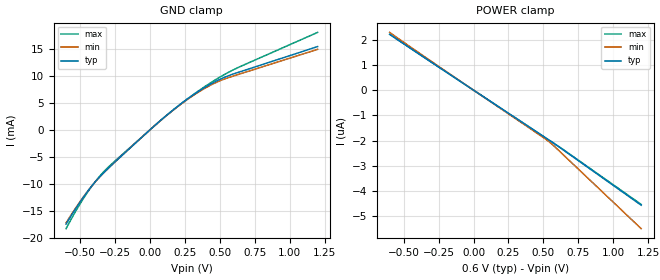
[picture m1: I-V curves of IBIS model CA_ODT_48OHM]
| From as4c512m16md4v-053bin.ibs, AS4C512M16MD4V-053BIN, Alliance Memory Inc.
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|   MODEL: CA_ODT_48OHM
[Model]   CA_ODT_48OHM
Model_type   Input
Vinl   = 0.080V
Vinh   = 0.220V
|   typ   min   max
C_comp   0.525pF   0.473pF   0.578pF
[Voltage Range]   0.600V   0.570V   0.650V
[Temperature Range]   25.0   85.0   -25.0
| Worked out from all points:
|   GND clamp passes 1 mA (typ) near -0.04 V on its own axis
[GND Clamp]
|   Voltage   I(typ)   I(min)   I(max)
-600mV    -17.5mA    -17.27mA   -18.35mA
-530mV    -14.57mA   -14.46mA   -15.04mA
-460mV    -11.92mA   -11.89mA   -12.11mA
-390mV    -9.606mA   -9.625mA   -9.577mA
-330mV    -7.942mA   -7.95mA    -7.761mA
40mV      935.3uA    924.7uA    918.6uA
160mV     3.582mA    3.536mA    3.549mA
280mV     5.954mA    5.86mA     5.974mA
420mV     8.293mA    8.109mA    8.504mA
550mV     9.935mA    9.604mA    10.52mA
650mV     10.83mA    10.44mA    11.8mA
1.2V      15.47mA    14.96mA    18.1mA
[POWER Clamp]
|   Voltage   I(typ)   I(min)   I(max)
-600mV    2.209uA    2.286uA    2.21uA
540mV     -1.977uA   -2.04uA    -1.975uA
650mV     -2.398uA   -2.599uA   -2.382uA
1.2V      -4.555uA   -5.484uA   -4.524uA
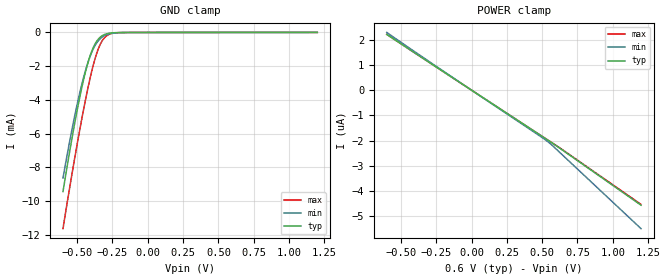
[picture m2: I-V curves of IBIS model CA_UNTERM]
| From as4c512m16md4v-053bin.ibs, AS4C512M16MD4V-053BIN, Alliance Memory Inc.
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|   MODEL: CA_UNTERM
[Model]   CA_UNTERM
Model_type   Input
Vinl   = 0.080V
Vinh   = 0.220V
|   typ   min   max
C_comp   0.525pF   0.473pF   0.578pF
[Voltage Range]   0.600V   0.570V   0.650V
[Temperature Range]   25.0   85.0   -25.0
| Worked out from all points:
|   GND clamp passes 1 mA (typ) near -0.39 V on its own axis
[GND Clamp]
|   Voltage   I(typ)   I(min)   I(max)
-600mV    -9.434mA   -8.63mA    -11.64mA
-550mV    -6.93mA    -6.337mA   -9.071mA
-510mV    -5.067mA   -4.664mA   -7.116mA
-470mV    -3.391mA   -3.183mA   -5.263mA
-430mV    -1.992mA   -1.958mA   -3.554mA
-400mV    -1.191mA   -1.248mA   -2.417mA
-360mV    -504.2uA   -602.3uA   -1.204mA
-330mV    -235.6uA   -319.5uA   -599.3uA
-290mV    -77.05uA   -125.7uA   -190.3uA
-250mV    -23.77uA   -46.49uA   -52uA
-170mV    -2.45uA    -6.01uA    -3.627uA
1.2V      4.4uA      4.55uA     4.397uA
[POWER Clamp]
|   Voltage   I(typ)   I(min)   I(max)
-600mV    2.209uA    2.286uA    2.21uA
540mV     -1.977uA   -2.04uA    -1.975uA
650mV     -2.398uA   -2.599uA   -2.382uA
1.2V      -4.555uA   -5.484uA   -4.524uA
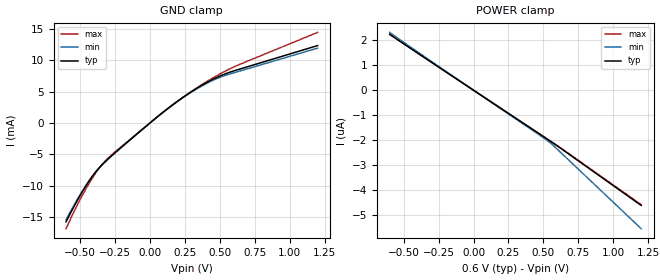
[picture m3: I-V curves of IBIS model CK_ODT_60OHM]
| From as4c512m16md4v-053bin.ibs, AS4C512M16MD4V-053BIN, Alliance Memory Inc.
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|   MODEL: CK_ODT_60OHM
[Model]   CK_ODT_60OHM
Model_type   Input
Vinl   = 0.080V
Vinh   = 0.220V
|   typ   min   max
C_comp   0.528pF   0.475pF   0.581pF
[Voltage Range]   0.600V   0.570V   0.650V
[Temperature Range]   25.0   85.0   -25.0
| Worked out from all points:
|   GND clamp passes 1 mA (typ) near -0.05 V on its own axis
[GND Clamp]
|   Voltage   I(typ)   I(min)   I(max)
-600mV    -15.8mA    -15.46mA   -16.9mA
-520mV    -12.4mA    -12.23mA   -13.13mA
-450mV    -9.763mA   -9.724mA   -10.22mA
-390mV    -7.874mA   -7.904mA   -8.065mA
-330mV    -6.397mA   -6.421mA   -6.325mA
-250mV    -4.771mA   -4.761mA   -4.631mA
20mV      376.5uA    372.3uA    369.3uA
240mV     4.156mA    4.096mA    4.15mA
400mV     6.391mA    6.258mA    6.53mA
540mV     7.862mA    7.608mA    8.298mA
650mV     8.663mA    8.348mA    9.44mA
1.2V      12.38mA    11.97mA    14.48mA
[POWER Clamp]
|   Voltage   I(typ)   I(min)   I(max)
-600mV    2.234uA    2.311uA    2.235uA
540mV     -1.999uA   -2.062uA   -1.998uA
650mV     -2.425uA   -2.626uA   -2.409uA
1.2V      -4.606uA   -5.535uA   -4.574uA
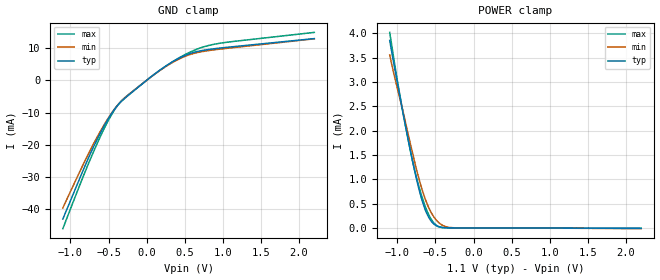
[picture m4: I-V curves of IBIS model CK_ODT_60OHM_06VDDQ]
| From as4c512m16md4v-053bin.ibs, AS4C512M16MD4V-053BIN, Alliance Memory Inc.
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|   MODEL: CK_ODT_60OHM_06VDDQ
[Model]   CK_ODT_60OHM_06VDDQ
Model_type   Input
Vinl   = 0.080V
Vinh   = 0.220V
|   typ   min   max
C_comp   0.528pF   0.475pF   0.581pF
[Voltage Range]   1.100V   1.060V   1.170V
[Temperature Range]   25.0   125.0   -40.0
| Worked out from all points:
|   GND clamp passes 1 mA (typ) near -0.05 V on its own axis
|   POWER clamp passes 1 mA (typ) near -0.75 V on its own axis
[GND Clamp]
|   Voltage   I(typ)   I(min)   I(max)
-1.1V     -42.96mA   -39.51mA   -45.94mA
-710mV    -21.23mA   -20.25mA   -22.82mA
-580mV    -15.08mA   -14.65mA   -16.02mA
-470mV    -10.63mA   -10.48mA   -11.04mA
-320mV    -6.286mA   -6.193mA   -6.103mA
40mV      761.1uA    731.7uA    743.1uA
240mV     4.234mA    4.083mA    4.196mA
440mV     7.005mA    6.763mA    7.142mA
600mV     8.511mA    8.193mA    9.042mA
770mV     9.38mA     9.038mA    10.5mA
1.05V     10.2mA     9.888mA    11.77mA
2.2V      12.91mA    12.84mA    14.83mA
[POWER Clamp]
|   Voltage   I(typ)   I(min)   I(max)
-1.1V     3.851mA    3.554mA    4.016mA
-1.01V    3.068mA    2.931mA    3.123mA
-940mV    2.475mA    2.485mA    2.495mA
-840mV    1.679mA    1.801mA    1.669mA
-770mV    1.153mA    1.339mA    1.17mA
-700mV    699.8uA    918.7uA    757.8uA
-630mV    358.7uA    578.1uA    426.1uA
-560mV    148.8uA    328uA      188.9uA
-490mV    45.81uA    162.6uA    57.53uA
-390mV    5.639uA    40.34uA    5.673uA
-260mV    1.093uA    3.432uA    1.039uA
2.2V      -8.447uA   -15.17uA   -8.228uA
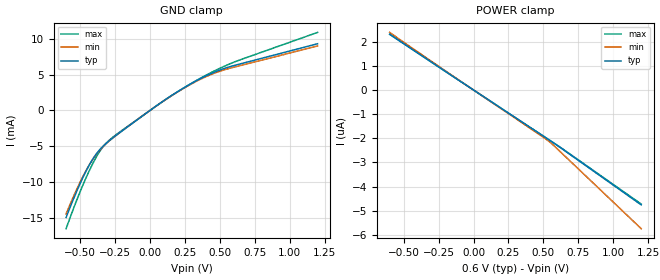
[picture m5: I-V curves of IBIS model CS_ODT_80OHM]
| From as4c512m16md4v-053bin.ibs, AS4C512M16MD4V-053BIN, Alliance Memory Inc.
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|   MODEL: CS_ODT_80OHM
[Model]   CS_ODT_80OHM
Model_type   Input
Vinl   = 0.080V
Vinh   = 0.220V
|   typ   min   max
C_comp   0.564pF   0.508pF   0.620pF
[Voltage Range]   0.600V   0.570V   0.650V
[Temperature Range]   25.0   85.0   -25.0
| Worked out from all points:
|   GND clamp passes 1 mA (typ) near -0.07 V on its own axis
[GND Clamp]
|   Voltage   I(typ)   I(min)   I(max)
-600mV    -14.89mA   -14.39mA   -16.44mA
-500mV    -10.19mA   -9.988mA   -11.32mA
-460mV    -8.546mA   -8.462mA   -9.488mA
-420mV    -7.112mA   -7.123mA   -7.813mA
-380mV    -5.948mA   -6.007mA   -6.345mA
-340mV    -5.057mA   -5.11mA    -5.164mA
-260mV    -3.731mA   -3.735mA   -3.635mA
120mV     1.635mA    1.615mA    1.615mA
260mV     3.345mA    3.295mA    3.348mA
400mV     4.791mA    4.692mA    4.895mA
580mV     6.135mA    5.915mA    6.553mA
1.2V      9.286mA    8.978mA    10.86mA
[POWER Clamp]
|   Voltage   I(typ)   I(min)   I(max)
-600mV    2.308uA    2.386uA    2.308uA
540mV     -2.065uA   -2.13uA    -2.064uA
650mV     -2.505uA   -2.717uA   -2.488uA
1.2V      -4.759uA   -5.745uA   -4.723uA
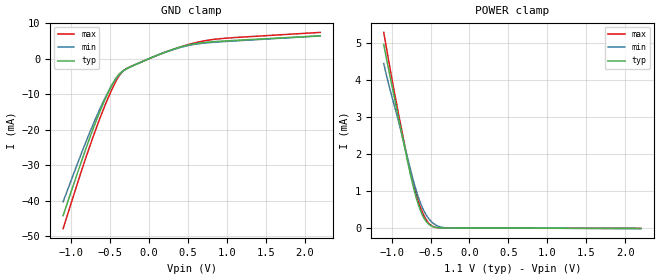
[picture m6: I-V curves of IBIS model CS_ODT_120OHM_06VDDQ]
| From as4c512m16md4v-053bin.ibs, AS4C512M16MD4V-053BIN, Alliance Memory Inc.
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|   MODEL: CS_ODT_120OHM_06VDDQ
[Model]   CS_ODT_120OHM_06VDDQ
Model_type   Input
Vinl   = 0.080V
Vinh   = 0.220V
|   typ   min   max
C_comp   0.564pF   0.508pF   0.620pF
[Voltage Range]   1.100V   1.060V   1.170V
[Temperature Range]   25.0   125.0   -40.0
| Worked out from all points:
|   GND clamp passes 1 mA (typ) near -0.10 V on its own axis
|   POWER clamp passes 1 mA (typ) near -0.71 V on its own axis
[GND Clamp]
|   Voltage   I(typ)   I(min)   I(max)
-1.1V     -44.13mA   -40.22mA   -47.8mA
-820mV    -26.05mA   -24.09mA   -28.6mA
-700mV    -18.84mA   -17.68mA   -21.02mA
-600mV    -13.37mA   -12.76mA   -15.17mA
-510mV    -8.964mA   -8.811mA   -10.39mA
-440mV    -6.09mA    -6.219mA   -7.105mA
-370mV    -4.088mA   -4.273mA   -4.461mA
-310mV    -3.11mA    -3.172mA   -3.089mA
200mV     1.793mA    1.729mA    1.771mA
580mV     4.181mA    4.027mA    4.414mA
970mV     4.999mA    4.838mA    5.75mA
2.2V      6.458mA    6.423mA    7.417mA
[POWER Clamp]
|   Voltage   I(typ)   I(min)   I(max)
-1.1V     4.96mA     4.444mA    5.287mA
-1.04V    4.311mA    3.913mA    4.562mA
-940mV    3.275mA    3.119mA    3.408mA
-820mV    2.064mA    2.11mA     2.117mA
-750mV    1.376mA    1.524mA    1.451mA
-690mV    869.2uA    1.061mA    964.3uA
-630mV    479.1uA    684.3uA    568.6uA
-570mV    224.3uA    406.8uA    279.7uA
-500mV    69.96uA    197.1uA    86.74uA
-400mV    8.221uA    49.73uA    8.449uA
-280mV    1.305uA    5.057uA    1.216uA
2.2V      -8.728uA   -15.86uA   -8.498uA
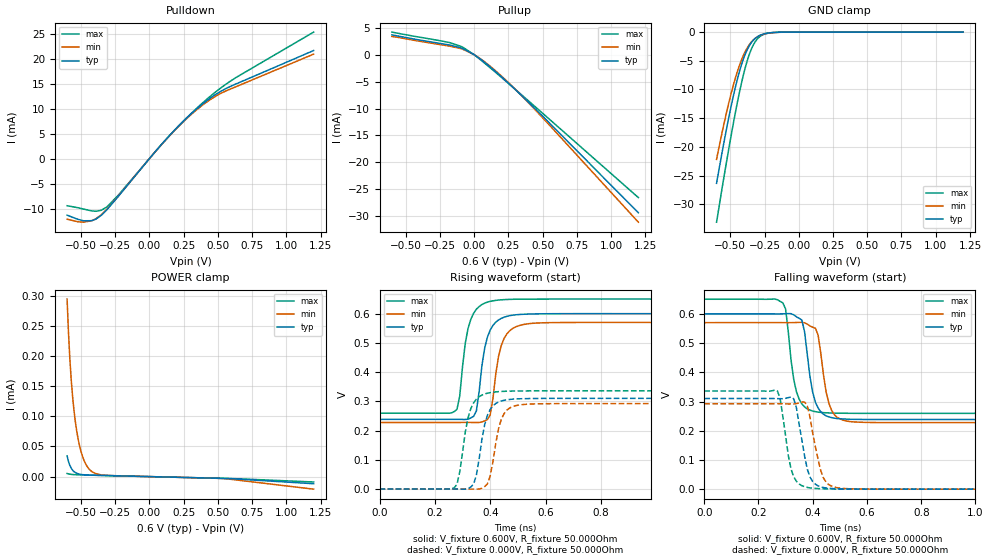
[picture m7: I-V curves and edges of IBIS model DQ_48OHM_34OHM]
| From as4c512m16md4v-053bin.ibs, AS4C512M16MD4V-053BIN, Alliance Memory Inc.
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|   MODEL: DQ_48OHM_34OHM
[Model]   DQ_48OHM_34OHM
Model_type   I/O
Polarity   Non-Inverting
Enable   Active-High
Vinl   = 0.080V
Vinh   = 0.220V
Vmeas   = 0.150V
Vref   = 0.150V
Cref   = 0.000pF
Rref   = 50.000Ohm
|   typ   min   max
C_comp   0.875pF   0.788pF   0.963pF
[Voltage Range]   0.600V   0.570V   0.650V
[Temperature Range]   25.0   85.0   -25.0
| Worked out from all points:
|   slope of the pulldown table from 0 to 0.09 V, typ, clamps not added: 31.1 ohm
|   slope of the pullup table from 0 to 0.09 V, typ, clamps not added: 52.7 ohm
|   GND clamp passes 1 mA (typ) near -0.31 V on its own axis
|   rising waveform, V_fixture 0.600V, R_fixture 50.000Ohm: 20-80 % time 36.6ps typ, 36.8ps min, 35.3ps max; typ from 0.238 V to 0.6 V
|   falling waveform, V_fixture 0.600V, R_fixture 50.000Ohm: 20-80 % time 34.7ps typ, 35.1ps min, 33.3ps max; typ from 0.6 V to 0.238 V
|   rising waveform, V_fixture 0.000V, R_fixture 50.000Ohm: 20-80 % time 36.1ps typ, 35.9ps min, 36.7ps max; typ from 0 V to 0.31 V
|   falling waveform, V_fixture 0.000V, R_fixture 50.000Ohm: 20-80 % time 37ps typ, 39.2ps min, 34.1ps max; typ from 0.31 V to 0 V
[Pulldown]
|   Voltage   I(typ)   I(min)   I(max)
-600mV    -11.29mA   -12.1mA    -9.399mA
-480mV    -12.41mA   -12.69mA   -10.07mA
-420mV    -12.4mA    -12.4mA    -10.44mA
-350mV    -11.31mA   -11.2mA    -10.3mA
-310mV    -10.22mA   -10.13mA   -9.646mA
-230mV    -7.655mA   -7.604mA   -7.404mA
130mV     4.124mA    4.073mA    4.076mA
270mV     8.079mA    7.954mA    8.096mA
400mV     11.19mA    10.96mA    11.44mA
490mV     12.95mA    12.6mA     13.49mA
580mV     14.32mA    13.81mA    15.3mA
1.2V      21.66mA    20.94mA    25.35mA
[Pullup]
|   Voltage   I(typ)   I(min)   I(max)
-600mV    3.666mA    3.362mA    4.175mA
-180mV    1.791mA    1.583mA    2.24mA
-100mV    1.29mA     1.134mA    1.576mA
0V        0A         0A         0A
80mV      -1.505mA   -1.39mA    -1.643mA
220mV     -4.564mA   -4.445mA   -4.653mA
400mV     -8.893mA   -8.998mA   -8.629mA
1.2V      -29.33mA   -31.08mA   -26.52mA
[GND Clamp]
|   Voltage   I(typ)   I(min)   I(max)
-600mV    -26.36mA   -22.19mA   -33.14mA
-550mV    -19.73mA   -16.43mA   -25.84mA
-510mV    -14.79mA   -12.27mA   -20.24mA
-470mV    -10.36mA   -8.615mA   -14.96mA
-430mV    -6.627mA   -5.609mA   -10.17mA
-390mV    -3.805mA   -3.349mA   -6.151mA
-360mV    -2.341mA   -2.151mA   -3.819mA
-320mV    -1.14mA    -1.122mA   -1.755mA
-280mV    -524.1uA   -555.5uA   -715.7uA
-230mV    -184.4uA   -215.6uA   -213.3uA
-140mV    -20.29uA   -29.99uA   -17.96uA
1.2V      6.836uA    7.386uA    6.714uA
[POWER Clamp]
|   Voltage   I(typ)   I(min)   I(max)
-600mV    34.27uA    294.1uA    5.169uA
-590mV    25uA       238.9uA    4.47uA
-570mV    13.84uA    160.6uA    3.674uA
-560mV    10.58uA    132.6uA    3.444uA
-540mV    6.655uA    91.24uA    3.146uA
-520mV    4.678uA    62.84uA    2.957uA
-490mV    3.339uA    35.2uA     2.748uA
-460mV    2.772uA    19.1uA     2.569uA
-420mV    2.39uA     8.47uA     2.342uA
-300mV    1.671uA    1.938uA    1.671uA
560mV     -3.13uA    -3.595uA   -3.086uA
1.2V      -11.8uA    -20.82uA   -8.926uA
[Ramp]
R_load = 50.000Ohm
|   typ   min   max
dV/dt_r   0.217V/40.000ps   0.205V/40.000ps   0.234V/30.000ps
dV/dt_f   0.217V/30.000ps   0.205V/30.000ps   0.234V/30.000ps
|Slew_r   5.425V/ns   5.134V/ns   7.810V/ns
|Slew_f   7.231V/ns   6.843V/ns   7.807V/ns
[Rising Waveform]
V_fixture = 0.600V
V_fixture_min = 0.570V
V_fixture_max = 0.650V
R_fixture = 50.000Ohm
L_fixture = 0.000nH
C_fixture = 0.000pF
|dV/dt_r   0.217V/40.000ps   0.205V/40.000ps   0.234V/30.000ps
|Slew_r   5.425V/ns   5.134V/ns   7.810V/ns
|   Time   V(typ)   V(min)   V(max)
0s        238.3mV    227.7mV    259.5mV
280ps     238.5mV    227.8mV    272.9mV
310ps     238.1mV    227.9mV    499.2mV
340ps     248.8mV    227.7mV    601.4mV
380ps     482.2mV    233.2mV    636.1mV
400ps     543.9mV    253.8mV    642.3mV
440ps     583.9mV    491mV      647.4mV
490ps     595.8mV    554mV      649.4mV
610ps     599.8mV    569.2mV    649.9mV
5ns       600mV      570mV      650mV
[Falling Waveform]
V_fixture = 0.600V
V_fixture_min = 0.570V
V_fixture_max = 0.650V
R_fixture = 50.000Ohm
L_fixture = 0.000nH
C_fixture = 0.000pF
|dV/dt_f   0.217V/30.000ps   0.205V/30.000ps   0.234V/30.000ps
|Slew_f   7.231V/ns   6.843V/ns   7.807V/ns
|   Time   V(typ)   V(min)   V(max)
0s        599.9mV    569.9mV    649.9mV
290ps     600.1mV    569.9mV    637.5mV
300ps     600.6mV    569.9mV    616.6mV
330ps     596.7mV    570.1mV    375.4mV
360ps     578.5mV    571mV      291.9mV
400ps     331.3mV    554.2mV    267.4mV
430ps     264.5mV    463.7mV    262.6mV
470ps     244.7mV    269.2mV    260.6mV
560ps     238.9mV    229.8mV    259.6mV
5ns       238.4mV    227.8mV    259.5mV
[Rising Waveform]
V_fixture = 0.000V
V_fixture_min = 0.000V
V_fixture_max = 0.000V
R_fixture = 50.000Ohm
L_fixture = 0.000nH
C_fixture = 0.000pF
|dV/dt_r   0.186V/30.000ps   0.175V/30.000ps   0.202V/30.000ps
|Slew_r   6.205V/ns   5.847V/ns   6.720V/ns
|   Time   V(typ)   V(min)   V(max)
0s        3.602uV    10.71uV    1.531uV
270ps     74.81uV    11.77uV    4.598mV
290ps     -195.7uV   38.56uV    59.19mV
330ps     7.147mV    -165.4uV   275.4mV
350ps     47.63mV    -365.8uV   307.6mV
390ps     252.4mV    17.62mV    328mV
430ps     297.9mV    206.1mV    333.3mV
470ps     306.5mV    277mV      334.9mV
570ps     309.9mV    291.5mV    335.9mV
5ns       310.2mV    292.4mV    336mV
[Falling Waveform]
V_fixture = 0.000V
V_fixture_min = 0.000V
V_fixture_max = 0.000V
R_fixture = 50.000Ohm
L_fixture = 0.000nH
C_fixture = 0.000pF
|dV/dt_f   0.186V/40.000ps   0.175V/40.000ps   0.202V/40.000ps
|Slew_f   4.653V/ns   4.385V/ns   5.039V/ns
|   Time   V(typ)   V(min)   V(max)
0s        310.2mV    292.3mV    335.9mV
270ps     309.8mV    292.4mV    336mV
280ps     309.5mV    292.4mV    309.2mV
310ps     313.3mV    291.7mV    115mV
330ps     309mV      291.7mV    42.43mV
380ps     68.48mV    284.9mV    5.936mV
410ps     16.83mV    144.2mV    2.465mV
450ps     4.049mV    23.33mV    915.8uV
540ps     435uV      1.228mV    53.84uV
5ns       3.996uV    11.07uV    1.926uV
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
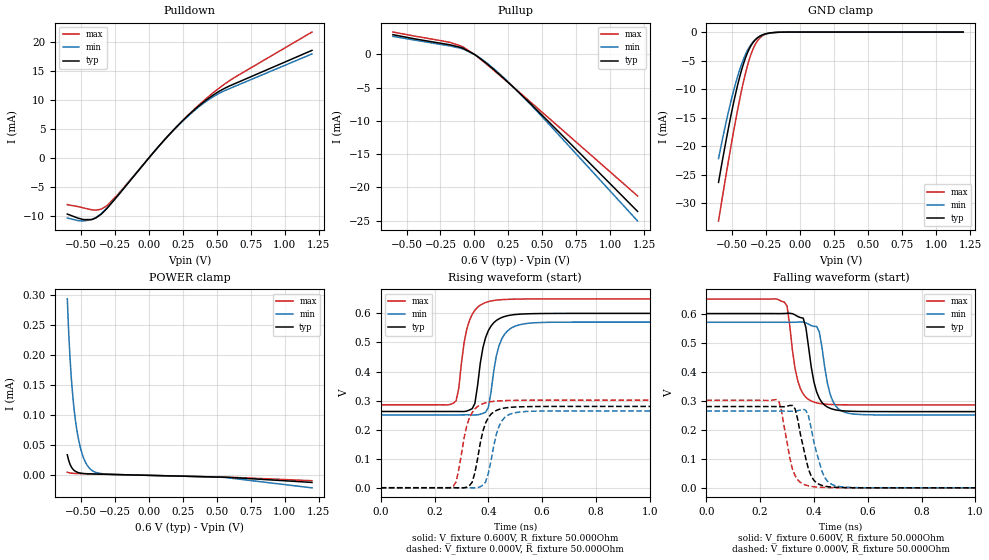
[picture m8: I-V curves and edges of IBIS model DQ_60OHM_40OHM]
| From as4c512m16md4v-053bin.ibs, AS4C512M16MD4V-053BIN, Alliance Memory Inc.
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|   MODEL: DQ_60OHM_40OHM
[Model]   DQ_60OHM_40OHM
Model_type   I/O
Polarity   Non-Inverting
Enable   Active-High
Vinl   = 0.080V
Vinh   = 0.220V
Vmeas   = 0.150V
Vref   = 0.150V
Cref   = 0.000pF
Rref   = 50.000Ohm
|   typ   min   max
C_comp   0.875pF   0.788pF   0.963pF
[Voltage Range]   0.600V   0.570V   0.650V
[Temperature Range]   25.0   85.0   -25.0
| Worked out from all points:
|   slope of the pulldown table from 0 to 0.09 V, typ, clamps not added: 36.2 ohm
|   slope of the pullup table from 0 to 0.09 V, typ, clamps not added: 65.2 ohm
|   GND clamp passes 1 mA (typ) near -0.31 V on its own axis
|   rising waveform, V_fixture 0.600V, R_fixture 50.000Ohm: 20-80 % time 39.9ps typ, 40ps min, 38.4ps max; typ from 0.262 V to 0.6 V
|   falling waveform, V_fixture 0.600V, R_fixture 50.000Ohm: 20-80 % time 37.2ps typ, 37.8ps min, 36.2ps max; typ from 0.6 V to 0.262 V
|   rising waveform, V_fixture 0.000V, R_fixture 50.000Ohm: 20-80 % time 39.3ps typ, 39.1ps min, 40.3ps max; typ from 0 V to 0.28 V
|   falling waveform, V_fixture 0.000V, R_fixture 50.000Ohm: 20-80 % time 41.1ps typ, 43.5ps min, 38.4ps max; typ from 0.28 V to 0 V
[Pulldown]
|   Voltage   I(typ)   I(min)   I(max)
-600mV    -9.677mA   -10.37mA   -8.055mA
-480mV    -10.64mA   -10.88mA   -8.627mA
-420mV    -10.62mA   -10.63mA   -8.948mA
-350mV    -9.692mA   -9.595mA   -8.829mA
-310mV    -8.758mA   -8.678mA   -8.266mA
-230mV    -6.56mA    -6.516mA   -6.345mA
130mV     3.534mA    3.49mA     3.493mA
270mV     6.924mA    6.817mA    6.938mA
400mV     9.592mA    9.392mA    9.8mA
490mV     11.1mA     10.8mA     11.56mA
580mV     12.28mA    11.83mA    13.12mA
1.2V      18.56mA    17.95mA    21.73mA
[Pullup]
|   Voltage   I(typ)   I(min)   I(max)
-600mV    2.969mA    2.718mA    3.369mA
-180mV    1.446mA    1.278mA    1.805mA
-100mV    1.041mA    915.1uA    1.27mA
0V        0A         0A         0A
70mV      -1.054mA   -969.1uA   -1.157mA
210mV     -3.5mA     -3.4mA     -3.575mA
400mV     -7.175mA   -7.266mA   -6.946mA
1.2V      -23.62mA   -25.07mA   -21.3mA
[GND Clamp]
|   Voltage   I(typ)   I(min)   I(max)
-600mV    -26.36mA   -22.19mA   -33.14mA
-550mV    -19.73mA   -16.43mA   -25.84mA
-510mV    -14.79mA   -12.27mA   -20.24mA
-470mV    -10.36mA   -8.615mA   -14.96mA
-430mV    -6.627mA   -5.609mA   -10.17mA
-390mV    -3.805mA   -3.349mA   -6.151mA
-360mV    -2.341mA   -2.151mA   -3.819mA
-320mV    -1.14mA    -1.122mA   -1.755mA
-280mV    -524.1uA   -555.5uA   -715.7uA
-230mV    -184.4uA   -215.6uA   -213.3uA
-140mV    -20.29uA   -29.99uA   -17.96uA
1.2V      6.836uA    7.386uA    6.714uA
[POWER Clamp]
|   Voltage   I(typ)   I(min)   I(max)
-600mV    34.27uA    294.1uA    5.169uA
-590mV    25uA       238.9uA    4.47uA
-570mV    13.84uA    160.6uA    3.674uA
-560mV    10.58uA    132.6uA    3.444uA
-540mV    6.655uA    91.24uA    3.146uA
-520mV    4.678uA    62.84uA    2.957uA
-490mV    3.339uA    35.2uA     2.748uA
-460mV    2.772uA    19.1uA     2.569uA
-420mV    2.39uA     8.47uA     2.342uA
-300mV    1.671uA    1.938uA    1.671uA
560mV     -3.13uA    -3.595uA   -3.086uA
1.2V      -11.8uA    -20.82uA   -8.926uA
[Ramp]
R_load = 50.000Ohm
|   typ   min   max
dV/dt_r   0.203V/40.000ps   0.192V/40.000ps   0.219V/40.000ps
dV/dt_f   0.202V/40.000ps   0.192V/40.000ps   0.219V/40.000ps
|Slew_r   5.064V/ns   4.790V/ns   5.470V/ns
|Slew_f   5.062V/ns   4.789V/ns   5.468V/ns
[Rising Waveform]
V_fixture = 0.600V
V_fixture_min = 0.570V
V_fixture_max = 0.650V
R_fixture = 50.000Ohm
L_fixture = 0.000nH
C_fixture = 0.000pF
|dV/dt_r   0.203V/40.000ps   0.192V/40.000ps   0.219V/40.000ps
|Slew_r   5.064V/ns   4.790V/ns   5.470V/ns
|   Time   V(typ)   V(min)   V(max)
0s        262.4mV    250.6mV    285.3mV
280ps     262.5mV    250.6mV    298.7mV
310ps     262.3mV    250.8mV    499.7mV
340ps     272.2mV    250.6mV    596.7mV
380ps     482.4mV    256.1mV    633.5mV
400ps     540.8mV    276.5mV    640.5mV
430ps     575.9mV    455.2mV    645.8mV
450ps     586mV      512.6mV    647.3mV
640ps     599.8mV    569.6mV    650mV
5ns       600mV      570mV      650mV
[Falling Waveform]
V_fixture = 0.600V
V_fixture_min = 0.570V
V_fixture_max = 0.650V
R_fixture = 50.000Ohm
L_fixture = 0.000nH
C_fixture = 0.000pF
|dV/dt_f   0.202V/40.000ps   0.192V/40.000ps   0.219V/40.000ps
|Slew_f   5.062V/ns   4.789V/ns   5.468V/ns
|   Time   V(typ)   V(min)   V(max)
0s        599.9mV    569.9mV    649.9mV
290ps     600.2mV    569.9mV    639.4mV
300ps     600.6mV    569.9mV    626.3mV
330ps     595.3mV    570.2mV    409.9mV
360ps     584.2mV    570.6mV    323.2mV
420ps     308mV      536.6mV    290.6mV
440ps     284.5mV    415.2mV    288.4mV
480ps     268.5mV    282.9mV    286.3mV
580ps     262.8mV    252.1mV    285.5mV
5ns       262.4mV    250.7mV    285.4mV
[Rising Waveform]
V_fixture = 0.000V
V_fixture_min = 0.000V
V_fixture_max = 0.000V
R_fixture = 50.000Ohm
L_fixture = 0.000nH
C_fixture = 0.000pF
|dV/dt_r   0.168V/40.000ps   0.159V/30.000ps   0.181V/40.000ps
|Slew_r   4.198V/ns   5.288V/ns   4.521V/ns
|   Time   V(typ)   V(min)   V(max)
0s        3.954uV    11.76uV    1.679uV
270ps     66.04uV    12.86uV    5.356mV
280ps     1.109uV    16.04uV    19.94mV
330ps     7.763mV    -182.5uV   241.1mV
350ps     51.78mV    -314.6uV   271.3mV
390ps     223.5mV    20.25mV    292.3mV
440ps     269.8mV    212.2mV    299mV
490ps     277.3mV    256.2mV    300.7mV
600ps     279.7mV    263.9mV    301.4mV
5ns       279.9mV    264.4mV    301.4mV
[Falling Waveform]
V_fixture = 0.000V
V_fixture_min = 0.000V
V_fixture_max = 0.000V
R_fixture = 50.000Ohm
L_fixture = 0.000nH
C_fixture = 0.000pF
|dV/dt_f   0.168V/40.000ps   0.159V/50.000ps   0.181V/40.000ps
|Slew_f   4.197V/ns   3.172V/ns   4.520V/ns
|   Time   V(typ)   V(min)   V(max)
0s        279.8mV    264.4mV    301.3mV
260ps     279.7mV    264.5mV    304.2mV
280ps     279.1mV    264.5mV    261.7mV
320ps     283.8mV    263.7mV    65.35mV
330ps     271.7mV    264.1mV    41.6mV
370ps     99.7mV     266.8mV    9.226mV
420ps     11.74mV    87.69mV    1.993mV
460ps     3.215mV    15.32mV    840.4uV
570ps     144.4uV    562.7uV    47.49uV
5ns       4.352uV    12.11uV    2.1uV
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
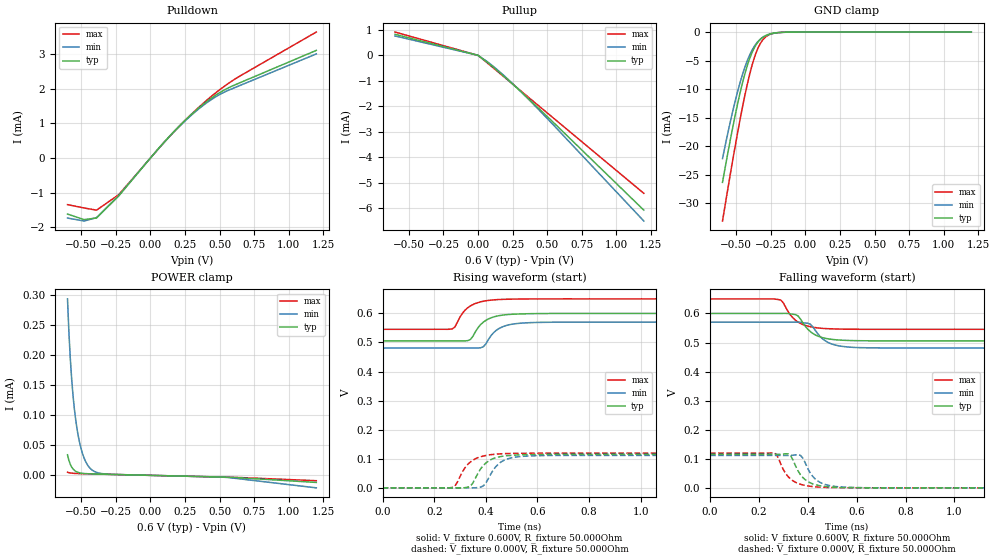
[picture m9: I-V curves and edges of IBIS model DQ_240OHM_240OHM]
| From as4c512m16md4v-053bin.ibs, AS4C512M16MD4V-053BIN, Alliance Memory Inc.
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|   MODEL: DQ_240OHM_240OHM
[Model]   DQ_240OHM_240OHM
Model_type   I/O
Polarity   Non-Inverting
Enable   Active-High
Vinl   = 0.080V
Vinh   = 0.220V
Vmeas   = 0.150V
Vref   = 0.150V
Cref   = 0.000pF
Rref   = 50.000Ohm
|   typ   min   max
C_comp   0.875pF   0.788pF   0.963pF
[Voltage Range]   0.600V   0.570V   0.650V
[Temperature Range]   25.0   85.0   -25.0
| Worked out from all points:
|   slope of the pulldown table from 0 to 0.09 V, typ, clamps not added: 217 ohm
|   slope of the pullup table from 0 to 0.09 V, typ, clamps not added: 243 ohm
|   GND clamp passes 1 mA (typ) near -0.31 V on its own axis
|   rising waveform, V_fixture 0.600V, R_fixture 50.000Ohm: 20-80 % time 58.4ps typ, 57.9ps min, 59.3ps max; typ from 0.505 V to 0.6 V
|   falling waveform, V_fixture 0.600V, R_fixture 50.000Ohm: 20-80 % time 65.6ps typ, 64.8ps min, 64.2ps max; typ from 0.6 V to 0.506 V
|   rising waveform, V_fixture 0.000V, R_fixture 50.000Ohm: 20-80 % time 57.1ps typ, 55.8ps min, 58.5ps max; typ from 0 V to 0.115 V
|   falling waveform, V_fixture 0.000V, R_fixture 50.000Ohm: 20-80 % time 56.5ps typ, 55.9ps min, 57.3ps max; typ from 0.115 V to 0 V
[Pulldown]
|   Voltage   I(typ)   I(min)   I(max)
-600mV    -1.616mA   -1.73mA    -1.344mA
-480mV    -1.776mA   -1.816mA   -1.44mA
-390mV    -1.729mA   -1.717mA   -1.503mA
-230mV    -1.095mA   -1.087mA   -1.059mA
0V        0A         0A         0A
140mV     633.6uA    626uA      626.7uA
270mV     1.157mA    1.139mA    1.159mA
390mV     1.571mA    1.54mA     1.603mA
490mV     1.854mA    1.803mA    1.931mA
580mV     2.05mA     1.977mA    2.191mA
1.2V      3.099mA    2.997mA    3.627mA
[Pullup]
|   Voltage   I(typ)   I(min)   I(max)
-600mV    822.9uA    759.1uA    913uA
0V        0A         0A         0A
70mV      -282.8uA   -260.1uA   -309.3uA
210mV     -927uA     -902.4uA   -941.1uA
400mV     -1.877mA   -1.909mA   -1.801mA
1.2V      -6.068mA   -6.495mA   -5.41mA
[GND Clamp]
|   Voltage   I(typ)   I(min)   I(max)
-600mV    -26.36mA   -22.19mA   -33.14mA
-550mV    -19.73mA   -16.43mA   -25.84mA
-510mV    -14.79mA   -12.27mA   -20.24mA
-470mV    -10.36mA   -8.615mA   -14.96mA
-430mV    -6.627mA   -5.609mA   -10.17mA
-390mV    -3.805mA   -3.349mA   -6.151mA
-360mV    -2.341mA   -2.151mA   -3.819mA
-320mV    -1.14mA    -1.122mA   -1.755mA
-280mV    -524.1uA   -555.5uA   -715.7uA
-230mV    -184.4uA   -215.6uA   -213.3uA
-140mV    -20.29uA   -29.99uA   -17.96uA
1.2V      6.836uA    7.386uA    6.714uA
[POWER Clamp]
|   Voltage   I(typ)   I(min)   I(max)
-600mV    34.27uA    294.1uA    5.169uA
-590mV    25uA       238.9uA    4.47uA
-570mV    13.84uA    160.6uA    3.674uA
-560mV    10.58uA    132.6uA    3.444uA
-540mV    6.655uA    91.24uA    3.146uA
-520mV    4.678uA    62.84uA    2.957uA
-490mV    3.339uA    35.2uA     2.748uA
-460mV    2.772uA    19.1uA     2.569uA
-420mV    2.39uA     8.47uA     2.342uA
-300mV    1.671uA    1.938uA    1.671uA
560mV     -3.13uA    -3.595uA   -3.086uA
1.2V      -11.8uA    -20.82uA   -8.926uA
[Ramp]
R_load = 50.000Ohm
|   typ   min   max
dV/dt_r   0.057V/60.000ps   0.053V/60.000ps   0.063V/60.000ps
dV/dt_f   0.057V/70.000ps   0.053V/60.000ps   0.063V/60.000ps
|Slew_r   0.946V/ns   0.891V/ns   1.048V/ns
|Slew_f   0.809V/ns   0.888V/ns   1.045V/ns
[Rising Waveform]
V_fixture = 0.600V
V_fixture_min = 0.570V
V_fixture_max = 0.650V
R_fixture = 50.000Ohm
L_fixture = 0.000nH
C_fixture = 0.000pF
|dV/dt_r   0.057V/60.000ps   0.053V/60.000ps   0.063V/60.000ps
|Slew_r   0.946V/ns   0.891V/ns   1.048V/ns
|   Time   V(typ)   V(min)   V(max)
0s        505.4mV    480.9mV    545.2mV
270ps     505.6mV    481mV      546.9mV
330ps     506.4mV    481.2mV    619.6mV
340ps     510.2mV    481.1mV    625.7mV
390ps     569.8mV    485.1mV    641.8mV
430ps     587.8mV    533.8mV    646.6mV
470ps     594.7mV    555.7mV    648.5mV
540ps     598.4mV    566.7mV    649.6mV
700ps     599.8mV    569.8mV    650mV
5ns       600mV      570mV      650mV
[Falling Waveform]
V_fixture = 0.600V
V_fixture_min = 0.570V
V_fixture_max = 0.650V
R_fixture = 50.000Ohm
L_fixture = 0.000nH
C_fixture = 0.000pF
|dV/dt_f   0.057V/70.000ps   0.053V/60.000ps   0.063V/60.000ps
|Slew_f   0.809V/ns   0.888V/ns   1.045V/ns
|   Time   V(typ)   V(min)   V(max)
0s        599.9mV    569.9mV    649.9mV
290ps     600.1mV    570mV      645.8mV
330ps     598.4mV    570.1mV    593.4mV
350ps     596.2mV    570.2mV    576.5mV
400ps     545.7mV    566.3mV    556.4mV
420ps     531.4mV    554.3mV    552.7mV
460ps     516.7mV    513mV      548.6mV
510ps     509.8mV    491.8mV    546.7mV
750ps     505.6mV    481.2mV    545.4mV
5ns       505.5mV    481mV      545.4mV
[Rising Waveform]
V_fixture = 0.000V
V_fixture_min = 0.000V
V_fixture_max = 0.000V
R_fixture = 50.000Ohm
L_fixture = 0.000nH
C_fixture = 0.000pF
|dV/dt_r   0.069V/60.000ps   0.067V/50.000ps   0.072V/60.000ps
|Slew_r   1.155V/ns   1.339V/ns   1.194V/ns
|   Time   V(typ)   V(min)   V(max)
0s        7.736uV    22.9uV     3.255uV
270ps     29.31uV    23.09uV    1.448mV
280ps     9.641uV    25.42uV    6.026mV
340ps     5.809mV    -71.89uV   88.89mV
380ps     65.45mV    2.627mV    106.8mV
400ps     85.35mV    16.57mV    111.2mV
440ps     103.8mV    74.29mV    115.9mV
490ps     111mV      101.1mV    118mV
710ps     115.4mV    111.5mV    119.3mV
5ns       115.5mV    111.6mV    119.4mV
[Falling Waveform]
V_fixture = 0.000V
V_fixture_min = 0.000V
V_fixture_max = 0.000V
R_fixture = 50.000Ohm
L_fixture = 0.000nH
C_fixture = 0.000pF
|dV/dt_f   0.069V/50.000ps   0.067V/60.000ps   0.072V/60.000ps
|Slew_f   1.385V/ns   1.115V/ns   1.194V/ns
|   Time   V(typ)   V(min)   V(max)
0s        115.4mV    111.5mV    119.4mV
260ps     115.4mV    111.6mV    120.4mV
270ps     115.2mV    111.6mV    115.9mV
320ps     116.7mV    111.2mV    38.13mV
360ps     58.04mV    114.2mV    15.21mV
380ps     35.14mV    101.9mV    9.847mV
430ps     11.09mV    30.71mV    3.541mV
480ps     3.822mV    9.529mV    1.309mV
720ps     27uV       37.18uV    43.42uV
5ns       8.032uV    23.11uV    3.516uV
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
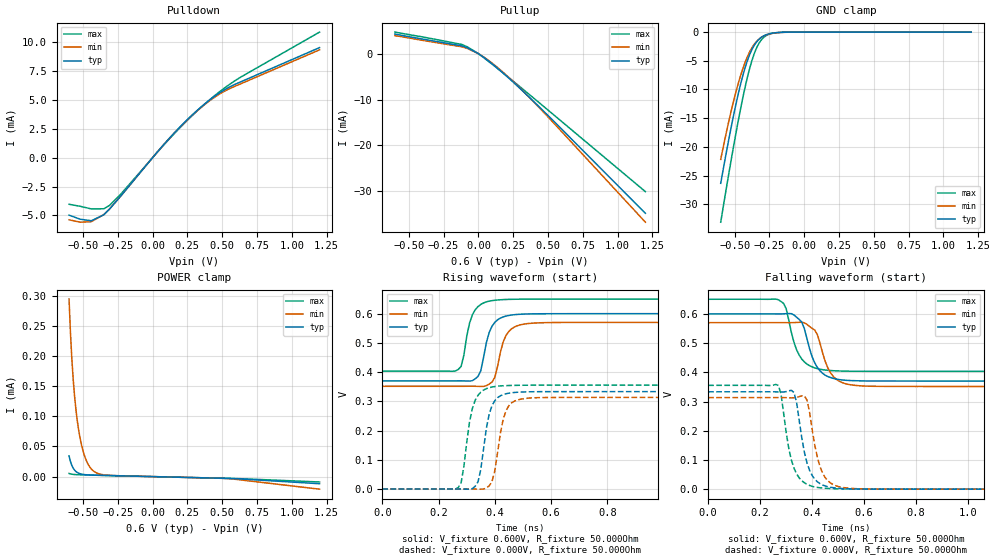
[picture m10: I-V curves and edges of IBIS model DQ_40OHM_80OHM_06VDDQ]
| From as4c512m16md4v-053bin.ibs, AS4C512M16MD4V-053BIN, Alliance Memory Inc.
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|   MODEL: DQ_40OHM_80OHM_06VDDQ
[Model]   DQ_40OHM_80OHM_06VDDQ
Model_type   I/O
Polarity   Non-Inverting
Enable   Active-High
Vinl   = 0.080V
Vinh   = 0.220V
Vmeas   = 0.150V
Vref   = 0.150V
Cref   = 0.000pF
Rref   = 50.000Ohm
|   typ   min   max
C_comp   0.875pF   0.788pF   0.963pF
[Voltage Range]   0.600V   0.570V   0.650V
[Temperature Range]   25.0   85.0   -25.0
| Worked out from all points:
|   slope of the pulldown table from 0 to 0.09 V, typ, clamps not added: 71.2 ohm
|   slope of the pullup table from 0 to 0.09 V, typ, clamps not added: 44.8 ohm
|   GND clamp passes 1 mA (typ) near -0.31 V on its own axis
|   rising waveform, V_fixture 0.600V, R_fixture 50.000Ohm: 20-80 % time 36.1ps typ, 37ps min, 34.4ps max; typ from 0.37 V to 0.6 V
|   falling waveform, V_fixture 0.600V, R_fixture 50.000Ohm: 20-80 % time 52.8ps typ, 52.2ps min, 50.3ps max; typ from 0.6 V to 0.37 V
|   rising waveform, V_fixture 0.000V, R_fixture 50.000Ohm: 20-80 % time 33.6ps typ, 33.9ps min, 34.4ps max; typ from 0 V to 0.333 V
|   falling waveform, V_fixture 0.000V, R_fixture 50.000Ohm: 20-80 % time 44.1ps typ, 44.4ps min, 44ps max; typ from 0.333 V to 0 V
[Pulldown]
|   Voltage   I(typ)   I(min)   I(max)
-600mV    -4.969mA   -5.373mA   -4.029mA
-520mV    -5.322mA   -5.579mA   -4.203mA
-440mV    -5.456mA   -5.535mA   -4.431mA
-350mV    -4.934mA   -4.919mA   -4.417mA
-310mV    -4.458mA   -4.447mA   -4.135mA
-230mV    -3.338mA   -3.338mA   -3.174mA
130mV     1.8mA      1.791mA    1.748mA
270mV     3.53mA     3.504mA    3.472mA
400mV     4.896mA    4.836mA    4.903mA
490mV     5.671mA    5.569mA    5.785mA
580mV     6.277mA    6.116mA    6.562mA
1.2V      9.525mA    9.333mA    10.87mA
[Pullup]
|   Voltage   I(typ)   I(min)   I(max)
-600mV    4.267mA    3.904mA    4.699mA
-120mV    1.7mA      1.495mA    2.011mA
-80mV     1.289mA    1.134mA    1.496mA
0V        0A         0A         0A
80mV      -1.767mA   -1.632mA   -1.852mA
220mV     -5.374mA   -5.228mA   -5.255mA
410mV     -10.79mA   -10.91mA   -10.01mA
1.2V      -34.79mA   -36.73mA   -30.07mA
[GND Clamp]
|   Voltage   I(typ)   I(min)   I(max)
-600mV    -26.36mA   -22.19mA   -33.14mA
-550mV    -19.73mA   -16.43mA   -25.84mA
-510mV    -14.79mA   -12.27mA   -20.24mA
-470mV    -10.36mA   -8.615mA   -14.96mA
-430mV    -6.627mA   -5.609mA   -10.17mA
-390mV    -3.805mA   -3.349mA   -6.151mA
-360mV    -2.341mA   -2.151mA   -3.819mA
-320mV    -1.14mA    -1.122mA   -1.755mA
-280mV    -524.1uA   -555.5uA   -715.7uA
-230mV    -184.4uA   -215.6uA   -213.3uA
-140mV    -20.29uA   -29.99uA   -17.96uA
1.2V      6.836uA    7.386uA    6.714uA
[POWER Clamp]
|   Voltage   I(typ)   I(min)   I(max)
-600mV    34.27uA    294.1uA    5.169uA
-590mV    25uA       238.9uA    4.47uA
-570mV    13.84uA    160.6uA    3.674uA
-560mV    10.58uA    132.6uA    3.444uA
-540mV    6.655uA    91.24uA    3.146uA
-520mV    4.678uA    62.84uA    2.957uA
-490mV    3.339uA    35.2uA     2.748uA
-460mV    2.772uA    19.1uA     2.569uA
-420mV    2.39uA     8.47uA     2.342uA
-300mV    1.671uA    1.938uA    1.671uA
560mV     -3.13uA    -3.595uA   -3.086uA
1.2V      -11.8uA    -20.82uA   -8.926uA
[Ramp]
R_load = 50.000Ohm
|   typ   min   max
dV/dt_r   0.138V/30.000ps   0.131V/40.000ps   0.148V/40.000ps
dV/dt_f   0.138V/60.000ps   0.131V/50.000ps   0.148V/50.000ps
|Slew_r   4.603V/ns   3.279V/ns   3.702V/ns
|Slew_f   2.300V/ns   2.621V/ns   2.960V/ns
[Rising Waveform]
V_fixture = 0.600V
V_fixture_min = 0.570V
V_fixture_max = 0.650V
R_fixture = 50.000Ohm
L_fixture = 0.000nH
C_fixture = 0.000pF
|dV/dt_r   0.138V/30.000ps   0.131V/40.000ps   0.148V/40.000ps
|Slew_r   4.603V/ns   3.279V/ns   3.702V/ns
|   Time   V(typ)   V(min)   V(max)
0s        369.9mV    351.4mV    403.2mV
270ps     370.1mV    351.5mV    409.2mV
280ps     370.1mV    351.5mV    419.3mV
320ps     370.7mV    351.7mV    595.5mV
350ps     404.4mV    351mV      631.6mV
390ps     557mV      366mV      644.6mV
430ps     589mV      503.9mV    648.2mV
470ps     596.5mV    554.4mV    649.3mV
580ps     599.8mV    569.3mV    649.9mV
5ns       600mV      570mV      650mV
[Falling Waveform]
V_fixture = 0.600V
V_fixture_min = 0.570V
V_fixture_max = 0.650V
R_fixture = 50.000Ohm
L_fixture = 0.000nH
C_fixture = 0.000pF
|dV/dt_f   0.138V/60.000ps   0.131V/50.000ps   0.148V/50.000ps
|Slew_f   2.300V/ns   2.621V/ns   2.960V/ns
|   Time   V(typ)   V(min)   V(max)
0s        599.9mV    569.9mV    649.9mV
270ps     599.8mV    570mV      648.3mV
300ps     600.7mV    569.8mV    617.7mV
330ps     596.2mV    570.1mV    502.3mV
360ps     571.8mV    571.2mV    445.2mV
410ps     432.1mV    544.4mV    415mV
480ps     379.4mV    386.9mV    405.4mV
540ps     372.1mV    358.5mV    403.8mV
670ps     370.1mV    351.8mV    403.4mV
5ns       369.9mV    351.5mV    403.3mV
[Rising Waveform]
V_fixture = 0.000V
V_fixture_min = 0.000V
V_fixture_max = 0.000V
R_fixture = 50.000Ohm
L_fixture = 0.000nH
C_fixture = 0.000pF
|dV/dt_r   0.200V/30.000ps   0.188V/40.000ps   0.213V/40.000ps
|Slew_r   6.665V/ns   4.701V/ns   5.331V/ns
|   Time   V(typ)   V(min)   V(max)
0s        5.555uV    16.44uV    2.366uV
270ps     131.6uV    14.89uV    4.893mV
280ps     81.51uV    19.16uV    21.04mV
320ps     1.402mV    63.02uV    275.3mV
340ps     23.77mV    -455.7uV   320.4mV
390ps     285.1mV    25.17mV    348.9mV
420ps     319.2mV    192mV      352.7mV
460ps     329.3mV    295.2mV    354.4mV
550ps     333mV      312.4mV    355.4mV
5ns       333.3mV    313.4mV    355.4mV
[Falling Waveform]
V_fixture = 0.000V
V_fixture_min = 0.000V
V_fixture_max = 0.000V
R_fixture = 50.000Ohm
L_fixture = 0.000nH
C_fixture = 0.000pF
|dV/dt_f   0.200V/40.000ps   0.188V/40.000ps   0.213V/50.000ps
|Slew_f   4.998V/ns   4.700V/ns   4.264V/ns
|   Time   V(typ)   V(min)   V(max)
0s        333.2mV    313.4mV    355.4mV
270ps     332.8mV    313.5mV    355mV
320ps     338.4mV    312.6mV    99.5mV
340ps     297.5mV    314mV      52.6mV
380ps     89.93mV    304.7mV    16.69mV
420ps     25.23mV    109mV      6mV
440ps     14.31mV    55.08mV    3.803mV
490ps     4.093mV    12.05mV    1.358mV
610ps     321.3uV    696.9uV    62.66uV
5ns       6.179uV    17.05uV    3.001uV
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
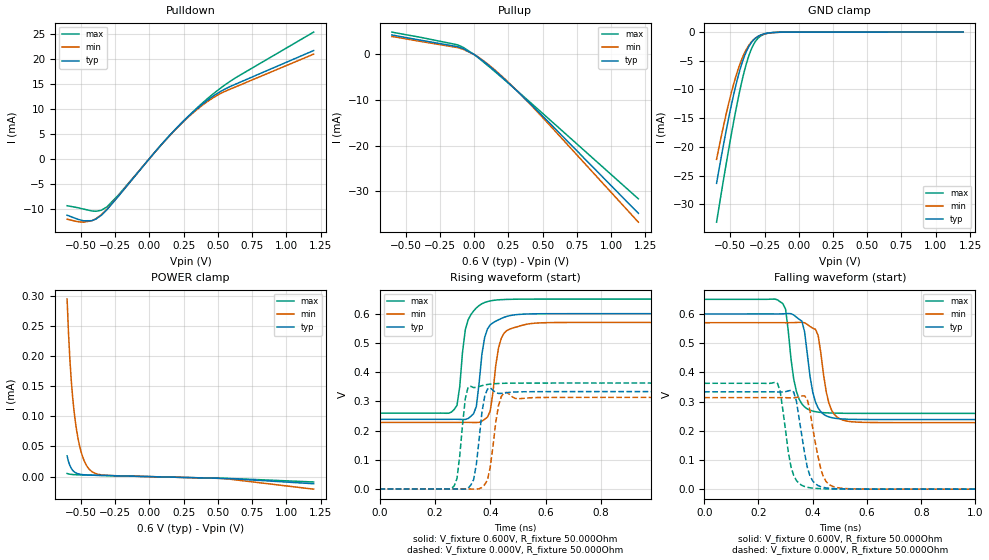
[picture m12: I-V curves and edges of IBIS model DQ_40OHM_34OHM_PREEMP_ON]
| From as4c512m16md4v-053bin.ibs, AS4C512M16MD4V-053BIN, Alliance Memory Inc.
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|   MODEL: DQ_40OHM_34OHM_PREEMP_ON
[Model]   DQ_40OHM_34OHM_PREEMP_ON
Model_type   I/O
Polarity   Non-Inverting
Enable   Active-High
Vinl   = 0.080V
Vinh   = 0.220V
Vmeas   = 0.150V
Vref   = 0.150V
Cref   = 0.000pF
Rref   = 50.000Ohm
|   typ   min   max
C_comp   0.875pF   0.788pF   0.963pF
[Voltage Range]   0.600V   0.570V   0.650V
[Temperature Range]   25.0   85.0   -25.0
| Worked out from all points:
|   slope of the pulldown table from 0 to 0.09 V, typ, clamps not added: 31.1 ohm
|   slope of the pullup table from 0 to 0.09 V, typ, clamps not added: 44.8 ohm
|   GND clamp passes 1 mA (typ) near -0.31 V on its own axis
|   rising waveform, V_fixture 0.600V, R_fixture 50.000Ohm: 20-80 % time 29.6ps typ, 31.1ps min, 30.1ps max; typ from 0.238 V to 0.6 V
|   falling waveform, V_fixture 0.600V, R_fixture 50.000Ohm: 20-80 % time 35ps typ, 35.2ps min, 33.4ps max; typ from 0.6 V to 0.238 V
|   rising waveform, V_fixture 0.000V, R_fixture 50.000Ohm: 20-80 % time 24.4ps typ, 26.6ps min, 23.1ps max; typ from 0 V to 0.333 V
|   falling waveform, V_fixture 0.000V, R_fixture 50.000Ohm: 20-80 % time 37ps typ, 39ps min, 34.2ps max; typ from 0.333 V to 0 V
[Pulldown]
|   Voltage   I(typ)   I(min)   I(max)
-600mV    -11.29mA   -12.1mA    -9.399mA
-480mV    -12.41mA   -12.69mA   -10.07mA
-420mV    -12.4mA    -12.4mA    -10.44mA
-350mV    -11.31mA   -11.2mA    -10.3mA
-310mV    -10.22mA   -10.13mA   -9.646mA
-230mV    -7.655mA   -7.604mA   -7.404mA
130mV     4.124mA    4.073mA    4.076mA
270mV     8.079mA    7.954mA    8.096mA
400mV     11.19mA    10.96mA    11.44mA
490mV     12.95mA    12.6mA     13.49mA
580mV     14.32mA    13.81mA    15.3mA
1.2V      21.66mA    20.94mA    25.35mA
[Pullup]
|   Voltage   I(typ)   I(min)   I(max)
-600mV    4.267mA    3.904mA    4.889mA
-120mV    1.7mA      1.495mA    2.101mA
-80mV     1.289mA    1.134mA    1.562mA
0V        0A         0A         0A
80mV      -1.767mA   -1.632mA   -1.932mA
220mV     -5.374mA   -5.228mA   -5.492mA
410mV     -10.79mA   -10.91mA   -10.49mA
1.2V      -34.79mA   -36.73mA   -31.61mA
[GND Clamp]
|   Voltage   I(typ)   I(min)   I(max)
-600mV    -26.36mA   -22.19mA   -33.14mA
-550mV    -19.73mA   -16.43mA   -25.84mA
-510mV    -14.79mA   -12.27mA   -20.24mA
-470mV    -10.36mA   -8.615mA   -14.96mA
-430mV    -6.627mA   -5.609mA   -10.17mA
-390mV    -3.805mA   -3.349mA   -6.151mA
-360mV    -2.341mA   -2.151mA   -3.819mA
-320mV    -1.14mA    -1.122mA   -1.755mA
-280mV    -524.1uA   -555.5uA   -715.7uA
-230mV    -184.4uA   -215.6uA   -213.3uA
-140mV    -20.29uA   -29.99uA   -17.96uA
1.2V      6.836uA    7.386uA    6.714uA
[POWER Clamp]
|   Voltage   I(typ)   I(min)   I(max)
-600mV    34.27uA    294.1uA    5.169uA
-590mV    25uA       238.9uA    4.47uA
-570mV    13.84uA    160.6uA    3.674uA
-560mV    10.58uA    132.6uA    3.444uA
-540mV    6.655uA    91.24uA    3.146uA
-520mV    4.678uA    62.84uA    2.957uA
-490mV    3.339uA    35.2uA     2.748uA
-460mV    2.772uA    19.1uA     2.569uA
-420mV    2.39uA     8.47uA     2.342uA
-300mV    1.671uA    1.938uA    1.671uA
560mV     -3.13uA    -3.595uA   -3.086uA
1.2V      -11.8uA    -20.82uA   -8.926uA
[Ramp]
R_load = 50.000Ohm
|   typ   min   max
dV/dt_r   0.217V/30.000ps   0.205V/30.000ps   0.234V/30.000ps
dV/dt_f   0.217V/30.000ps   0.205V/30.000ps   0.234V/30.000ps
|Slew_r   7.233V/ns   6.845V/ns   7.810V/ns
|Slew_f   7.231V/ns   6.843V/ns   7.807V/ns
[Rising Waveform]
V_fixture = 0.600V
V_fixture_min = 0.570V
V_fixture_max = 0.650V
R_fixture = 50.000Ohm
L_fixture = 0.000nH
C_fixture = 0.000pF
|dV/dt_r   0.217V/30.000ps   0.205V/30.000ps   0.234V/30.000ps
|Slew_r   7.233V/ns   6.845V/ns   7.810V/ns
|   Time   V(typ)   V(min)   V(max)
0s        238.3mV    227.7mV    259.5mV
270ps     238.5mV    227.8mV    272.1mV
290ps     238.2mV    227.8mV    351.2mV
310ps     237.9mV    227.9mV    544.8mV
330ps     248.6mV    227.7mV    596.4mV
350ps     282.6mV    227.3mV    619.7mV
400ps     561.6mV    266.4mV    643.7mV
430ps     579.1mV    482.6mV    647.5mV
620ps     599.9mV    569.5mV    650mV
5ns       600mV      570mV      650mV
[Falling Waveform]
V_fixture = 0.600V
V_fixture_min = 0.570V
V_fixture_max = 0.650V
R_fixture = 50.000Ohm
L_fixture = 0.000nH
C_fixture = 0.000pF
|dV/dt_f   0.217V/30.000ps   0.205V/30.000ps   0.234V/30.000ps
|Slew_f   7.231V/ns   6.843V/ns   7.807V/ns
|   Time   V(typ)   V(min)   V(max)
0s        599.9mV    569.9mV    649.9mV
290ps     600.2mV    570mV      635mV
300ps     600.8mV    570mV      615.9mV
330ps     596.5mV    570.2mV    376.8mV
360ps     575.4mV    571.3mV    291.8mV
420ps     277.8mV    526.3mV    263.7mV
440ps     256.5mV    391.5mV    261.9mV
480ps     243mV      255.5mV    260.3mV
570ps     238.7mV    229.3mV    259.6mV
5ns       238.4mV    227.8mV    259.5mV
[Rising Waveform]
V_fixture = 0.000V
V_fixture_min = 0.000V
V_fixture_max = 0.000V
R_fixture = 50.000Ohm
L_fixture = 0.000nH
C_fixture = 0.000pF
|dV/dt_r   0.200V/30.000ps   0.188V/30.000ps   0.218V/20.000ps
|Slew_r   6.665V/ns   6.268V/ns   10.875V/ns
|   Time   V(typ)   V(min)   V(max)
0s        3.602uV    10.71uV    1.531uV
270ps     115.8uV    12.13uV    10.58mV
280ps     2.572uV    16.61uV    35.74mV
320ps     3.148mV    -17.87uV   348.2mV
340ps     31.43mV    -609.1uV   347.1mV
380ps     316.8mV    14.53mV    356mV
410ps     338mV      145.4mV    359.9mV
430ps     326.9mV    285.3mV    361.1mV
460ps     329.6mV    330.2mV    361.9mV
5ns       333.3mV    313.4mV    362.5mV
[Falling Waveform]
V_fixture = 0.000V
V_fixture_min = 0.000V
V_fixture_max = 0.000V
R_fixture = 50.000Ohm
L_fixture = 0.000nH
C_fixture = 0.000pF
|dV/dt_f   0.200V/40.000ps   0.188V/40.000ps   0.217V/40.000ps
|Slew_f   4.998V/ns   4.700V/ns   5.437V/ns
|   Time   V(typ)   V(min)   V(max)
0s        333.2mV    313.4mV    362.5mV
270ps     333mV      313.5mV    362.6mV
280ps     332.7mV    313.5mV    334.9mV
310ps     336.4mV    312.9mV    126.7mV
330ps     332.1mV    312.9mV    46.59mV
380ps     74.79mV    306.7mV    6.485mV
410ps     18.03mV    156.8mV    2.697mV
450ps     4.274mV    25.42mV    958.8uV
540ps     445.4uV    1.297mV    143.8uV
5ns       4.001uV    10.81uV    1.94uV
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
